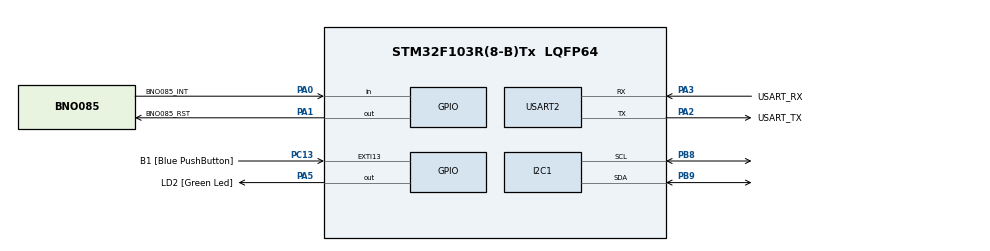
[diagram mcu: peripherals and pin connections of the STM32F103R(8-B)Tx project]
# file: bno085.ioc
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I2C1.I2C_Mode=I2C_Fast
Mcu.Family=STM32F1
Mcu.Name=STM32F103R(8-B)Tx
Mcu.Package=LQFP64
NVIC.EXTI15_10_IRQn=true\:0\:0\:false\:false\:true\:true\:true\:true
NVIC.PriorityGroup=NVIC_PRIORITYGROUP_4
PA0-WKUP.GPIO_Label=BNO085_INT
PA0-WKUP.GPIO_PuPd=GPIO_PULLUP
PA0-WKUP.Signal=GPIO_Input
PA1.GPIO_Label=BNO085_RST
PA1.GPIO_ModeDefaultOutputPP=GPIO_MODE_OUTPUT_PP
PA1.PinState=GPIO_PIN_SET
PA1.Signal=GPIO_Output
PA13.GPIO_Label=TMS
PA13.Mode=Serial_Wire
PA13.Signal=SYS_JTMS-SWDIO
PA14.GPIO_Label=TCK
PA14.Mode=Serial_Wire
PA14.Signal=SYS_JTCK-SWCLK
PA2.GPIO_Label=USART_TX
PA2.GPIO_Mode=GPIO_MODE_AF_PP
PA2.GPIO_PuPd=GPIO_NOPULL
PA2.GPIO_Speed=GPIO_SPEED_FREQ_LOW
PA2.Mode=Asynchronous
PA2.Signal=USART2_TX
PA3.GPIO_Label=USART_RX
PA3.GPIO_Mode=GPIO_MODE_AF_PP
PA3.GPIO_PuPd=GPIO_NOPULL
PA3.GPIO_Speed=GPIO_SPEED_FREQ_LOW
PA3.Mode=Asynchronous
PA3.Signal=USART2_RX
PA5.GPIO_Label=LD2 [Green Led]
PA5.GPIO_ModeDefaultOutputPP=GPIO_MODE_OUTPUT_PP
PA5.GPIO_PuPd=GPIO_NOPULL
PA5.GPIO_Speed=GPIO_SPEED_FREQ_LOW
PA5.Signal=GPIO_Output
PB3.GPIO_Label=SWO
PB3.Signal=SYS_JTDO-TRACESWO
PB8.Mode=I2C
PB8.Signal=I2C1_SCL
PB9.Mode=I2C
PB9.Signal=I2C1_SDA
PC13-TAMPER-RTC.GPIO_Label=B1 [Blue PushButton]
PC13-TAMPER-RTC.GPIO_PuPd=GPIO_NOPULL
PC13-TAMPER-RTC.Signal=GPXTI13
PC14-OSC32_IN.Mode=LSE-External-Oscillator
PC14-OSC32_IN.Signal=RCC_OSC32_IN
PC15-OSC32_OUT.Mode=LSE-External-Oscillator
PC15-OSC32_OUT.Signal=RCC_OSC32_OUT
PD0-OSC_IN.Mode=HSE-External-Clock-Source
PD0-OSC_IN.Signal=RCC_OSC_IN
PD1-OSC_OUT.Mode=HSE-External-Clock-Source
PD1-OSC_OUT.Signal=RCC_OSC_OUT
ProjectManager.HeapSize=0x200
ProjectManager.StackSize=0x400
ProjectManager.TargetToolchain=STM32CubeIDE
RCC.AHBFreq_Value=64000000
RCC.APB1CLKDivider=RCC_HCLK_DIV2
RCC.APB1Freq_Value=32000000
RCC.APB1TimFreq_Value=64000000
RCC.APB2Freq_Value=64000000
RCC.APB2TimFreq_Value=64000000
RCC.HCLKFreq_Value=64000000
RCC.PLLMUL=RCC_PLL_MUL16
RCC.RTCClockSelection=RCC_RTCCLKSOURCE_LSE
RCC.SYSCLKFreq_VALUE=64000000
RCC.SYSCLKSource=RCC_SYSCLKSOURCE_PLLCLK
RCC.USBFreq_Value=64000000
USART2.VirtualMode=VM_ASYNC
board=NUCLEO-F103RB

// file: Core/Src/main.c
/* USER CODE BEGIN Header */
/**
  ******************************************************************************
  * @file           : main.c
  * @brief          : Main program body
  ******************************************************************************
  */
/* USER CODE END Header */

#include "main.h"
#include "gpio.h"
#include "i2c.h"
#include "usart.h"
#include "bno085_stm32.h"

#include <stdio.h>
#include <string.h>

void SystemClock_Config(void);

/* USER CODE BEGIN 0 */
extern UART_HandleTypeDef huart2;
/* USER CODE END 0 */

int main(void)
{
    /* Reset peripherals, init Flash & SysTick */
    HAL_Init();

    /* Configure system clock */
    SystemClock_Config();

    /* Initialize peripherals */
    MX_GPIO_Init();
    MX_I2C1_Init();
    MX_USART2_UART_Init();

    /* USER CODE BEGIN 2 */

    /* UART sanity message */
    const char startMsg[] = "\r\nSTM32 + BNO085 booted\r\n";
    HAL_UART_Transmit(&huart2,
                      (uint8_t*)startMsg,
                      sizeof(startMsg) - 1,
                      HAL_MAX_DELAY);

    /* Initialize BNO085 + SH2 */
    BNO085_Init();

    /* USER CODE END 2 */

    /* Infinite loop */
    while (1)
    {
        /* Service SH2 / BNO085 */
        BNO085_Update();

        /* Small idle delay to avoid 100% CPU load */
        HAL_Delay(1);
    }
}

void SystemClock_Config(void)
{
    RCC_OscInitTypeDef RCC_OscInitStruct = {0};
    RCC_ClkInitTypeDef RCC_ClkInitStruct = {0};

    /* Use HSE (8 MHz) + PLL = 72 MHz */
    RCC_OscInitStruct.OscillatorType = RCC_OSCILLATORTYPE_HSE;
    RCC_OscInitStruct.HSEState = RCC_HSE_ON;
    RCC_OscInitStruct.HSEPredivValue = RCC_HSE_PREDIV_DIV1;
    RCC_OscInitStruct.PLL.PLLState = RCC_PLL_ON;
    RCC_OscInitStruct.PLL.PLLSource = RCC_PLLSOURCE_HSE;
    RCC_OscInitStruct.PLL.PLLMUL = RCC_PLL_MUL9;

    if (HAL_RCC_OscConfig(&RCC_OscInitStruct) != HAL_OK)
    {
        Error_Handler();
    }

    /* Configure clocks */
    RCC_ClkInitStruct.ClockType =
        RCC_CLOCKTYPE_HCLK | RCC_CLOCKTYPE_SYSCLK |
        RCC_CLOCKTYPE_PCLK1 | RCC_CLOCKTYPE_PCLK2;

    RCC_ClkInitStruct.SYSCLKSource = RCC_SYSCLKSOURCE_PLLCLK;
    RCC_ClkInitStruct.AHBCLKDivider = RCC_SYSCLK_DIV1;
    RCC_ClkInitStruct.APB1CLKDivider = RCC_HCLK_DIV2;
    RCC_ClkInitStruct.APB2CLKDivider = RCC_HCLK_DIV1;

    if (HAL_RCC_ClockConfig(&RCC_ClkInitStruct, FLASH_LATENCY_2) != HAL_OK)
    {
        Error_Handler();
    }
}

/**
  * @brief Error Handler
  */
void Error_Handler(void)
{
    __disable_irq();
    while (1)
    {
        /* Fatal error: stay here */
    }
}
